VERSION 5.8 ;
BUSBITCHARS "[]" ;
DIVIDERCHAR "/" ;
UNITS
    DATABASE MICRONS 1000 ;
END UNITS

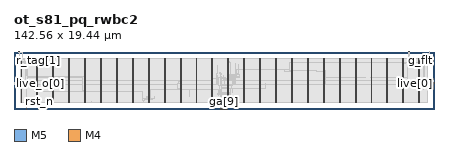
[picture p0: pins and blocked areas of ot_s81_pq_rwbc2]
MACRO ot_s81_pq_rwbc2
  FOREIGN ot_s81_pq_rwbc2 0 0 ;
  CLASS BLOCK ;
  SIZE 142.56 BY 19.44 ;
  PIN clk
    DIRECTION INPUT ;
    USE SIGNAL ;
    PORT
      LAYER M5 ;
        RECT  4.32 0 4.344 0.084 ;
    END
  END clk
  PIN g_flt
    DIRECTION INPUT ;
    USE SIGNAL ;
    PORT
      LAYER M5 ;
        RECT  141.12 19.356 141.144 19.44 ;
    END
  END g_flt
  PIN ga[0]
    DIRECTION OUTPUT ;
    USE SIGNAL ;
    PORT
      LAYER M5 ;
        RECT  70.128 0 70.152 0.084 ;
    END
  END ga[0]
  PIN ga[10]
    DIRECTION OUTPUT ;
    USE SIGNAL ;
    PORT
      LAYER M5 ;
        RECT  71.568 0 71.592 0.084 ;
    END
  END ga[10]
  PIN ga[11]
    DIRECTION OUTPUT ;
    USE SIGNAL ;
    PORT
      LAYER M5 ;
        RECT  71.712 0 71.736 0.084 ;
    END
  END ga[11]
  PIN ga[12]
    DIRECTION OUTPUT ;
    USE SIGNAL ;
    PORT
      LAYER M5 ;
        RECT  71.856 0 71.88 0.084 ;
    END
  END ga[12]
  PIN ga[13]
    DIRECTION OUTPUT ;
    USE SIGNAL ;
    PORT
      LAYER M5 ;
        RECT  72 0 72.024 0.084 ;
    END
  END ga[13]
  PIN ga[14]
    DIRECTION OUTPUT ;
    USE SIGNAL ;
    PORT
      LAYER M5 ;
        RECT  72.144 0 72.168 0.084 ;
    END
  END ga[14]
  PIN ga[15]
    DIRECTION OUTPUT ;
    USE SIGNAL ;
    PORT
      LAYER M5 ;
        RECT  72.288 0 72.312 0.084 ;
    END
  END ga[15]
  PIN ga[1]
    DIRECTION OUTPUT ;
    USE SIGNAL ;
    PORT
      LAYER M5 ;
        RECT  70.272 0 70.296 0.084 ;
    END
  END ga[1]
  PIN ga[2]
    DIRECTION OUTPUT ;
    USE SIGNAL ;
    PORT
      LAYER M5 ;
        RECT  70.416 0 70.44 0.084 ;
    END
  END ga[2]
  PIN ga[3]
    DIRECTION OUTPUT ;
    USE SIGNAL ;
    PORT
      LAYER M5 ;
        RECT  70.56 0 70.584 0.084 ;
    END
  END ga[3]
  PIN ga[4]
    DIRECTION OUTPUT ;
    USE SIGNAL ;
    PORT
      LAYER M5 ;
        RECT  70.704 0 70.728 0.084 ;
    END
  END ga[4]
  PIN ga[5]
    DIRECTION OUTPUT ;
    USE SIGNAL ;
    PORT
      LAYER M5 ;
        RECT  70.848 0 70.872 0.084 ;
    END
  END ga[5]
  PIN ga[6]
    DIRECTION OUTPUT ;
    USE SIGNAL ;
    PORT
      LAYER M5 ;
        RECT  70.992 0 71.016 0.084 ;
    END
  END ga[6]
  PIN ga[7]
    DIRECTION OUTPUT ;
    USE SIGNAL ;
    PORT
      LAYER M5 ;
        RECT  71.136 0 71.16 0.084 ;
    END
  END ga[7]
  PIN ga[8]
    DIRECTION OUTPUT ;
    USE SIGNAL ;
    PORT
      LAYER M5 ;
        RECT  71.28 0 71.304 0.084 ;
    END
  END ga[8]
  PIN ga[9]
    DIRECTION OUTPUT ;
    USE SIGNAL ;
    PORT
      LAYER M5 ;
        RECT  71.424 0 71.448 0.084 ;
    END
  END ga[9]
  PIN live[0]
    DIRECTION INPUT ;
    USE SIGNAL ;
    PORT
      LAYER M4 ;
        RECT  142.476 8.64 142.56 8.664 ;
    END
  END live[0]
  PIN live[1]
    DIRECTION INPUT ;
    USE SIGNAL ;
    PORT
      LAYER M4 ;
        RECT  142.476 8.784 142.56 8.808 ;
    END
  END live[1]
  PIN live[2]
    DIRECTION INPUT ;
    USE SIGNAL ;
    PORT
      LAYER M4 ;
        RECT  142.476 8.928 142.56 8.952 ;
    END
  END live[2]
  PIN live[3]
    DIRECTION INPUT ;
    USE SIGNAL ;
    PORT
      LAYER M4 ;
        RECT  142.476 9.072 142.56 9.096 ;
    END
  END live[3]
  PIN live_o[0]
    DIRECTION OUTPUT ;
    USE SIGNAL ;
    PORT
      LAYER M4 ;
        RECT  0 8.64 0.084 8.664 ;
    END
  END live_o[0]
  PIN live_o[1]
    DIRECTION OUTPUT ;
    USE SIGNAL ;
    PORT
      LAYER M4 ;
        RECT  0 8.784 0.084 8.808 ;
    END
  END live_o[1]
  PIN live_o[2]
    DIRECTION OUTPUT ;
    USE SIGNAL ;
    PORT
      LAYER M4 ;
        RECT  0 8.928 0.084 8.952 ;
    END
  END live_o[2]
  PIN live_o[3]
    DIRECTION OUTPUT ;
    USE SIGNAL ;
    PORT
      LAYER M4 ;
        RECT  0 9.072 0.084 9.096 ;
    END
  END live_o[3]
  PIN q2f
    DIRECTION OUTPUT ;
    USE SIGNAL ;
    PORT
      LAYER M5 ;
        RECT  72.432 0 72.456 0.084 ;
    END
  END q2f
  PIN r_e[0]
    DIRECTION INPUT ;
    USE SIGNAL ;
    PORT
      LAYER M5 ;
        RECT  1.968 19.356 1.992 19.44 ;
    END
  END r_e[0]
  PIN r_e[1]
    DIRECTION INPUT ;
    USE SIGNAL ;
    PORT
      LAYER M5 ;
        RECT  134.256 19.356 134.28 19.44 ;
    END
  END r_e[1]
  PIN r_tag[0]
    DIRECTION INPUT ;
    USE SIGNAL ;
    PORT
      LAYER M5 ;
        RECT  1.776 19.356 1.8 19.44 ;
    END
  END r_tag[0]
  PIN r_tag[1]
    DIRECTION INPUT ;
    USE SIGNAL ;
    PORT
      LAYER M5 ;
        RECT  1.872 19.356 1.896 19.44 ;
    END
  END r_tag[1]
  PIN r_tag[2]
    DIRECTION INPUT ;
    USE SIGNAL ;
    PORT
      LAYER M5 ;
        RECT  134.064 19.356 134.088 19.44 ;
    END
  END r_tag[2]
  PIN r_tag[3]
    DIRECTION INPUT ;
    USE SIGNAL ;
    PORT
      LAYER M5 ;
        RECT  134.16 19.356 134.184 19.44 ;
    END
  END r_tag[3]
  PIN r_v[0]
    DIRECTION INPUT ;
    USE SIGNAL ;
    PORT
      LAYER M5 ;
        RECT  1.68 19.356 1.704 19.44 ;
    END
  END r_v[0]
  PIN r_v[1]
    DIRECTION INPUT ;
    USE SIGNAL ;
    PORT
      LAYER M5 ;
        RECT  133.968 19.356 133.992 19.44 ;
    END
  END r_v[1]
  PIN rst_n
    DIRECTION INPUT ;
    USE SIGNAL ;
    PORT
      LAYER M5 ;
        RECT  8.64 0 8.664 0.084 ;
    END
  END rst_n
  PIN VDD
    DIRECTION INOUT ;
    USE POWER ;
    PORT
      LAYER M5 ;
        RECT  137.592 2.151 137.712 17.289 ;
        RECT  132.192 2.151 132.312 17.289 ;
        RECT  126.792 2.151 126.912 17.289 ;
        RECT  121.392 2.151 121.512 17.289 ;
        RECT  115.992 2.151 116.112 17.289 ;
        RECT  110.592 2.151 110.712 17.289 ;
        RECT  105.192 2.151 105.312 17.289 ;
        RECT  99.792 2.151 99.912 17.289 ;
        RECT  94.392 2.151 94.512 17.289 ;
        RECT  88.992 2.151 89.112 17.289 ;
        RECT  83.592 2.151 83.712 17.289 ;
        RECT  78.192 2.151 78.312 17.289 ;
        RECT  72.792 2.151 72.912 17.289 ;
        RECT  67.392 2.151 67.512 17.289 ;
        RECT  61.992 2.151 62.112 17.289 ;
        RECT  56.592 2.151 56.712 17.289 ;
        RECT  51.192 2.151 51.312 17.289 ;
        RECT  45.792 2.151 45.912 17.289 ;
        RECT  40.392 2.151 40.512 17.289 ;
        RECT  34.992 2.151 35.112 17.289 ;
        RECT  29.592 2.151 29.712 17.289 ;
        RECT  24.192 2.151 24.312 17.289 ;
        RECT  18.792 2.151 18.912 17.289 ;
        RECT  13.392 2.151 13.512 17.289 ;
        RECT  7.992 2.151 8.112 17.289 ;
        RECT  2.592 2.151 2.712 17.289 ;
    END
  END VDD
  PIN VSS
    DIRECTION INOUT ;
    USE GROUND ;
    PORT
      LAYER M5 ;
        RECT  137.4 2.137 137.52 17.303 ;
        RECT  132 2.137 132.12 17.303 ;
        RECT  126.6 2.137 126.72 17.303 ;
        RECT  121.2 2.137 121.32 17.303 ;
        RECT  115.8 2.137 115.92 17.303 ;
        RECT  110.4 2.137 110.52 17.303 ;
        RECT  105 2.137 105.12 17.303 ;
        RECT  99.6 2.137 99.72 17.303 ;
        RECT  94.2 2.137 94.32 17.303 ;
        RECT  88.8 2.137 88.92 17.303 ;
        RECT  83.4 2.137 83.52 17.303 ;
        RECT  78 2.137 78.12 17.303 ;
        RECT  72.6 2.137 72.72 17.303 ;
        RECT  67.2 2.137 67.32 17.303 ;
        RECT  61.8 2.137 61.92 17.303 ;
        RECT  56.4 2.137 56.52 17.303 ;
        RECT  51 2.137 51.12 17.303 ;
        RECT  45.6 2.137 45.72 17.303 ;
        RECT  40.2 2.137 40.32 17.303 ;
        RECT  34.8 2.137 34.92 17.303 ;
        RECT  29.4 2.137 29.52 17.303 ;
        RECT  24 2.137 24.12 17.303 ;
        RECT  18.6 2.137 18.72 17.303 ;
        RECT  13.2 2.137 13.32 17.303 ;
        RECT  7.8 2.137 7.92 17.303 ;
        RECT  2.4 2.137 2.52 17.303 ;
    END
  END VSS
  OBS
    LAYER RVTN ;
     RECT  2.16 2.16 140.4 2.295 ;
     RECT  2.16 2.565 140.4 2.835 ;
     RECT  2.16 3.105 140.4 3.375 ;
     RECT  2.16 3.645 140.4 3.915 ;
     RECT  2.16 4.185 140.4 4.455 ;
     RECT  2.16 4.725 140.4 4.995 ;
     RECT  2.16 5.265 140.4 5.535 ;
     RECT  2.16 5.805 140.4 6.075 ;
     RECT  2.16 6.345 140.4 6.615 ;
     RECT  2.16 6.885 140.4 7.155 ;
     RECT  2.16 7.425 140.4 7.695 ;
     RECT  2.16 7.965 140.4 8.235 ;
     RECT  2.16 8.505 140.4 8.775 ;
     RECT  2.16 9.045 140.4 9.315 ;
     RECT  2.16 9.585 140.4 9.855 ;
     RECT  2.16 10.125 140.4 10.395 ;
     RECT  2.16 10.665 140.4 10.935 ;
     RECT  2.16 11.205 140.4 11.475 ;
     RECT  2.16 11.745 140.4 12.015 ;
     RECT  2.16 12.285 140.4 12.555 ;
     RECT  2.16 12.825 140.4 13.095 ;
     RECT  2.16 13.365 140.4 13.635 ;
     RECT  2.16 13.905 140.4 14.175 ;
     RECT  2.16 14.445 140.4 14.715 ;
     RECT  2.16 14.985 140.4 15.255 ;
     RECT  2.16 15.525 140.4 15.795 ;
     RECT  2.16 16.065 140.4 16.335 ;
     RECT  2.16 16.605 140.4 16.875 ;
     RECT  2.16 17.145 140.4 17.28 ;
    LAYER RVTP ;
     RECT  2.16 2.295 140.4 2.565 ;
     RECT  2.16 2.835 140.4 3.105 ;
     RECT  2.16 3.375 140.4 3.645 ;
     RECT  2.16 3.915 140.4 4.185 ;
     RECT  2.16 4.455 140.4 4.725 ;
     RECT  2.16 4.995 140.4 5.265 ;
     RECT  2.16 5.535 140.4 5.805 ;
     RECT  2.16 6.075 140.4 6.345 ;
     RECT  2.16 6.615 140.4 6.885 ;
     RECT  2.16 7.155 140.4 7.425 ;
     RECT  2.16 7.695 140.4 7.965 ;
     RECT  2.16 8.235 140.4 8.505 ;
     RECT  2.16 8.775 140.4 9.045 ;
     RECT  2.16 9.315 140.4 9.585 ;
     RECT  2.16 9.855 140.4 10.125 ;
     RECT  2.16 10.395 140.4 10.665 ;
     RECT  2.16 10.935 140.4 11.205 ;
     RECT  2.16 11.475 140.4 11.745 ;
     RECT  2.16 12.015 140.4 12.285 ;
     RECT  2.16 12.555 140.4 12.825 ;
     RECT  2.16 13.095 140.4 13.365 ;
     RECT  2.16 13.635 140.4 13.905 ;
     RECT  2.16 14.175 140.4 14.445 ;
     RECT  2.16 14.715 140.4 14.985 ;
     RECT  2.16 15.255 140.4 15.525 ;
     RECT  2.16 15.795 140.4 16.065 ;
     RECT  2.16 16.335 140.4 16.605 ;
     RECT  2.16 16.875 140.4 17.145 ;
    LAYER M1 ;
     RECT  2.16 2.151 140.4 17.289 ;
    LAYER M2 ;
     RECT  0.103 8.316 0.535 8.334 ;
     RECT  0.535 8.316 2.16 8.532 ;
     RECT  2.16 2.151 140.4 17.289 ;
     RECT  140.4 16.92 140.819 16.938 ;
     RECT  140.4 9.09 141.179 9.576 ;
     RECT  141.179 9.558 142.403 9.576 ;
    LAYER M3 ;
     RECT  70.056 0.091 72.27 1.147 ;
     RECT  70.056 1.147 72.306 1.723 ;
     RECT  70.056 1.723 72.486 2.143 ;
     RECT  70.056 2.143 72.705 2.191 ;
     RECT  70.056 2.191 73.026 2.263 ;
     RECT  17.424 2.227 17.442 2.285 ;
     RECT  22.824 2.191 22.842 2.291 ;
     RECT  70.056 2.263 73.638 2.335 ;
     RECT  69.768 2.335 73.638 2.371 ;
     RECT  2.415 2.143 2.505 2.413 ;
     RECT  7.815 2.143 7.905 2.413 ;
     RECT  13.215 2.143 13.305 2.413 ;
     RECT  18.615 2.143 18.705 2.413 ;
     RECT  24.015 2.143 24.105 2.413 ;
     RECT  29.415 2.143 29.505 2.413 ;
     RECT  34.815 2.143 34.905 2.413 ;
     RECT  40.215 2.143 40.305 2.413 ;
     RECT  45.615 2.143 45.705 2.413 ;
     RECT  51.015 2.143 51.105 2.413 ;
     RECT  56.415 2.143 56.505 2.413 ;
     RECT  61.815 2.143 61.905 2.413 ;
     RECT  67.215 2.143 67.305 2.413 ;
     RECT  78.015 2.143 78.105 2.413 ;
     RECT  83.415 2.143 83.505 2.413 ;
     RECT  88.815 2.143 88.905 2.413 ;
     RECT  94.215 2.143 94.305 2.413 ;
     RECT  99.615 2.143 99.705 2.413 ;
     RECT  105.015 2.143 105.105 2.413 ;
     RECT  110.415 2.143 110.505 2.413 ;
     RECT  115.815 2.143 115.905 2.413 ;
     RECT  121.215 2.143 121.305 2.413 ;
     RECT  126.615 2.143 126.705 2.413 ;
     RECT  132.015 2.143 132.105 2.413 ;
     RECT  137.415 2.143 137.505 2.413 ;
     RECT  26.352 2.371 26.37 2.525 ;
     RECT  44.1 2.641 44.118 2.795 ;
     RECT  45.615 2.413 45.897 3.073 ;
     RECT  43.56 3.037 43.578 3.101 ;
     RECT  44.316 2.911 44.442 3.109 ;
     RECT  45.615 3.073 46.422 3.109 ;
     RECT  44.316 3.109 46.422 3.181 ;
     RECT  44.316 3.181 46.89 3.335 ;
     RECT  44.424 3.335 46.89 3.371 ;
     RECT  69.48 2.371 73.638 3.371 ;
     RECT  44.892 3.371 46.89 3.415 ;
     RECT  44.892 3.415 47.214 3.451 ;
     RECT  44.892 3.451 47.682 3.569 ;
     RECT  44.892 3.569 46.422 3.605 ;
     RECT  70.128 3.371 73.638 3.725 ;
     RECT  70.164 3.725 73.638 3.839 ;
     RECT  44.892 3.605 46.386 3.875 ;
     RECT  47.664 3.569 47.682 3.875 ;
     RECT  45.072 3.875 46.386 4.109 ;
     RECT  47.7 3.991 47.718 4.109 ;
     RECT  70.272 3.839 73.638 4.109 ;
     RECT  45.072 4.109 46.278 4.145 ;
     RECT  70.272 4.109 73.602 4.379 ;
     RECT  69.3 4.495 69.318 4.891 ;
     RECT  70.272 4.379 73.53 4.891 ;
     RECT  69.3 4.891 73.53 4.919 ;
     RECT  69.3 4.919 73.422 5.071 ;
     RECT  69.228 5.071 73.422 5.117 ;
     RECT  69.3 5.117 73.422 5.645 ;
     RECT  24.015 2.413 24.297 5.881 ;
     RECT  23.364 5.881 24.93 6.029 ;
     RECT  23.364 6.029 24.297 6.269 ;
     RECT  56.415 2.413 56.697 6.511 ;
     RECT  61.815 2.413 62.097 6.511 ;
     RECT  67.215 2.413 67.497 6.511 ;
     RECT  59.544 4.081 59.562 6.575 ;
     RECT  69.3 5.645 69.642 6.575 ;
     RECT  61.815 6.511 62.766 6.611 ;
     RECT  66.744 6.511 67.497 6.611 ;
     RECT  69.516 6.575 69.642 6.611 ;
     RECT  55.476 6.523 55.494 6.691 ;
     RECT  56.415 6.511 57.006 6.701 ;
     RECT  55.44 6.691 55.494 6.809 ;
     RECT  85.284 6.808 85.302 6.811 ;
     RECT  55.44 6.809 55.458 6.845 ;
     RECT  70.38 5.645 73.422 6.961 ;
     RECT  74.16 5.611 74.178 6.961 ;
     RECT  84.924 6.811 85.302 6.989 ;
     RECT  70.38 6.961 74.178 7.079 ;
     RECT  85.284 6.989 85.302 7.079 ;
     RECT  69.624 6.611 69.642 7.897 ;
     RECT  70.38 7.079 73.746 7.897 ;
     RECT  69.624 7.897 73.746 7.963 ;
     RECT  69.48 7.963 73.746 8.041 ;
     RECT  2.415 2.413 2.697 8.167 ;
     RECT  69.48 8.041 74.286 8.275 ;
     RECT  138.852 6.583 138.87 8.275 ;
     RECT  69.48 8.275 74.79 8.303 ;
     RECT  137.415 2.413 137.697 8.401 ;
     RECT  2.415 8.167 2.934 8.437 ;
     RECT  139.644 8.401 139.662 8.437 ;
     RECT  137.415 8.401 137.97 8.477 ;
     RECT  0.108 8.311 0.126 8.509 ;
     RECT  0.108 8.509 0.558 8.669 ;
     RECT  139.644 8.437 139.806 8.669 ;
     RECT  88.815 2.413 89.097 8.671 ;
     RECT  99.615 2.413 99.897 8.671 ;
     RECT  83.415 2.413 83.697 8.683 ;
     RECT  137.415 8.477 137.79 8.707 ;
     RECT  88.704 8.671 89.097 8.717 ;
     RECT  0.54 8.669 0.558 8.813 ;
     RECT  46.728 8.683 46.746 8.813 ;
     RECT  4.5 8.443 4.518 8.815 ;
     RECT  43.056 8.779 43.074 8.816 ;
     RECT  4.356 8.815 4.518 8.827 ;
     RECT  138.744 8.275 138.87 8.827 ;
     RECT  69.552 8.303 74.79 8.851 ;
     RECT  137.376 8.707 137.79 8.879 ;
     RECT  2.415 8.437 3.294 8.923 ;
     RECT  7.056 8.539 7.074 8.923 ;
     RECT  2.376 8.923 3.294 8.941 ;
     RECT  83.415 8.683 83.79 8.941 ;
     RECT  138.672 8.827 138.87 8.941 ;
     RECT  138.672 8.941 139.23 8.969 ;
     RECT  36.684 8.941 36.702 9.005 ;
     RECT  139.968 8.779 140.058 9.005 ;
     RECT  2.304 8.941 3.294 9.013 ;
     RECT  4.356 8.827 4.698 9.013 ;
     RECT  69.552 8.851 74.826 9.041 ;
     RECT  139.968 9.005 139.986 9.041 ;
     RECT  83.415 8.941 83.898 9.053 ;
     RECT  2.304 9.013 4.698 9.085 ;
     RECT  36.36 9.067 36.378 9.113 ;
     RECT  141.156 8.923 141.174 9.113 ;
     RECT  78.015 2.413 78.297 9.121 ;
     RECT  2.304 9.085 5.13 9.149 ;
     RECT  45.615 4.145 45.897 9.163 ;
     RECT  51.015 2.413 51.297 9.163 ;
     RECT  56.415 6.701 56.697 9.163 ;
     RECT  61.815 6.611 62.097 9.163 ;
     RECT  67.215 6.611 67.497 9.163 ;
     RECT  41.472 8.815 41.49 9.197 ;
     RECT  137.376 8.879 137.697 9.205 ;
     RECT  4.644 9.149 5.13 9.239 ;
     RECT  78.015 9.121 78.642 9.239 ;
     RECT  104.256 9.115 104.274 9.239 ;
     RECT  137.304 9.205 137.697 9.245 ;
     RECT  6.912 8.923 7.074 9.275 ;
     RECT  45.504 9.163 45.897 9.275 ;
     RECT  50.904 9.163 51.297 9.275 ;
     RECT  56.304 9.163 56.697 9.275 ;
     RECT  61.704 9.163 62.097 9.275 ;
     RECT  67.104 9.163 67.497 9.275 ;
     RECT  134.532 9.121 134.55 9.275 ;
     RECT  69.552 9.041 70.578 9.311 ;
     RECT  71.388 9.041 74.826 9.319 ;
     RECT  99.504 8.671 99.897 9.341 ;
     RECT  69.552 9.311 70.47 9.355 ;
     RECT  7.815 2.413 8.097 9.391 ;
     RECT  105.015 2.413 105.297 9.391 ;
     RECT  138.852 8.969 139.23 9.391 ;
     RECT  71.388 9.319 75.078 9.419 ;
     RECT  67.215 9.275 67.497 9.481 ;
     RECT  69.048 9.355 70.47 9.509 ;
     RECT  58.5 9.499 58.518 9.545 ;
     RECT  69.048 9.509 70.11 9.581 ;
     RECT  142.38 9.067 142.398 9.581 ;
     RECT  7.272 9.391 8.097 9.629 ;
     RECT  138.852 9.391 139.302 9.629 ;
     RECT  67.215 9.481 68.094 9.661 ;
     RECT  105.015 9.391 105.714 9.677 ;
     RECT  67.215 9.661 68.274 9.779 ;
     RECT  69.48 9.581 70.11 9.779 ;
     RECT  71.388 9.419 74.97 9.787 ;
     RECT  2.304 9.149 3.762 9.815 ;
     RECT  68.256 9.779 68.274 9.931 ;
     RECT  2.415 9.815 3.762 10.057 ;
     RECT  4.644 9.239 4.662 10.057 ;
     RECT  2.415 10.057 4.662 10.121 ;
     RECT  71.352 9.787 74.97 10.165 ;
     RECT  71.244 10.165 75.042 10.229 ;
     RECT  68.256 9.931 68.706 10.253 ;
     RECT  69.516 9.779 70.11 10.363 ;
     RECT  69.516 10.363 70.434 10.471 ;
     RECT  71.244 10.229 71.622 10.471 ;
     RECT  72.504 10.229 75.042 10.499 ;
     RECT  121.215 2.413 121.497 10.561 ;
     RECT  68.688 10.253 68.706 10.589 ;
     RECT  69.516 10.471 71.622 10.589 ;
     RECT  69.624 10.589 71.514 10.625 ;
     RECT  119.304 10.597 119.322 10.637 ;
     RECT  120.852 10.561 121.497 10.637 ;
     RECT  69.624 10.625 70.434 10.661 ;
     RECT  72.504 10.499 74.214 10.733 ;
     RECT  74.988 10.499 75.042 10.741 ;
     RECT  76.536 10.705 76.554 10.741 ;
     RECT  13.215 2.413 13.497 10.831 ;
     RECT  22.104 10.831 22.122 10.843 ;
     RECT  71.244 10.625 71.478 10.859 ;
     RECT  13.104 10.831 13.497 10.877 ;
     RECT  21.996 10.843 22.122 10.877 ;
     RECT  69.948 10.661 70.218 10.895 ;
     RECT  72.576 10.733 74.214 10.967 ;
     RECT  74.988 10.741 76.626 10.967 ;
     RECT  21.996 10.877 22.014 11.039 ;
     RECT  72.615 10.967 74.214 11.275 ;
     RECT  74.988 10.967 75.618 11.275 ;
     RECT  76.536 10.967 76.626 11.281 ;
     RECT  71.244 10.859 71.262 11.399 ;
     RECT  72.615 11.275 75.618 11.399 ;
     RECT  76.536 11.281 76.698 11.543 ;
     RECT  70.2 10.895 70.218 11.551 ;
     RECT  72.615 11.399 74.106 11.669 ;
     RECT  76.536 11.543 76.554 11.669 ;
     RECT  72.615 11.669 73.746 11.705 ;
     RECT  75.312 11.399 75.618 11.821 ;
     RECT  75.312 11.821 76.158 11.885 ;
     RECT  70.2 11.551 70.326 11.939 ;
     RECT  68.832 11.419 68.85 11.947 ;
     RECT  68.832 11.947 68.994 11.975 ;
     RECT  69.912 12.019 69.93 12.091 ;
     RECT  69.804 12.091 69.93 12.479 ;
     RECT  69.804 12.479 69.822 12.515 ;
     RECT  94.215 2.413 94.497 12.859 ;
     RECT  99.615 9.341 99.897 12.991 ;
     RECT  94.215 12.859 94.662 13.037 ;
     RECT  99.504 12.991 99.897 13.037 ;
     RECT  102.6 12.859 102.618 13.037 ;
     RECT  93.384 13.051 93.402 13.091 ;
     RECT  91.836 12.859 91.854 13.297 ;
     RECT  91.764 13.297 91.854 13.331 ;
     RECT  91.764 13.331 91.782 13.373 ;
     RECT  68.976 11.975 68.994 14.639 ;
     RECT  76.14 11.885 76.158 14.639 ;
     RECT  76.068 14.791 76.086 15.017 ;
     RECT  134.604 14.881 134.622 15.025 ;
     RECT  130.536 14.989 130.554 15.089 ;
     RECT  3.96 10.121 4.662 15.163 ;
     RECT  134.424 15.025 134.622 15.421 ;
     RECT  3.492 15.163 4.662 15.449 ;
     RECT  75.312 11.885 75.33 15.557 ;
     RECT  132.015 2.413 132.297 15.565 ;
     RECT  3.492 15.449 4.626 15.601 ;
     RECT  72.615 11.705 73.53 15.629 ;
     RECT  3.42 15.601 4.626 15.719 ;
     RECT  138.852 9.629 139.194 15.719 ;
     RECT  132.015 15.565 133.002 15.763 ;
     RECT  133.812 15.421 134.622 15.763 ;
     RECT  132.015 15.763 134.622 15.773 ;
     RECT  137.415 9.245 137.697 15.787 ;
     RECT  133.488 15.773 134.622 15.821 ;
     RECT  138.852 15.719 138.87 15.827 ;
     RECT  2.415 10.121 2.697 15.871 ;
     RECT  3.42 15.719 3.834 15.871 ;
     RECT  137.415 15.787 137.898 15.871 ;
     RECT  138.744 15.835 138.762 15.871 ;
     RECT  4.608 15.719 4.626 15.989 ;
     RECT  137.415 15.871 138.762 15.989 ;
     RECT  72.615 15.629 73.206 16.097 ;
     RECT  130.536 16.069 130.554 16.169 ;
     RECT  2.415 15.871 3.834 16.259 ;
     RECT  2.415 16.259 3.654 16.645 ;
     RECT  133.488 15.821 133.83 16.681 ;
     RECT  134.604 15.821 134.622 16.681 ;
     RECT  133.488 16.681 134.622 16.799 ;
     RECT  137.415 15.989 138.078 16.979 ;
     RECT  7.815 9.629 8.097 17.027 ;
     RECT  13.215 10.877 13.497 17.027 ;
     RECT  18.615 2.413 18.897 17.027 ;
     RECT  24.015 6.269 24.297 17.027 ;
     RECT  29.415 2.413 29.697 17.027 ;
     RECT  34.815 2.413 35.097 17.027 ;
     RECT  40.215 2.413 40.497 17.027 ;
     RECT  45.615 9.275 45.897 17.027 ;
     RECT  51.015 9.275 51.297 17.027 ;
     RECT  56.415 9.275 56.697 17.027 ;
     RECT  61.815 9.275 62.097 17.027 ;
     RECT  67.215 9.779 67.497 17.027 ;
     RECT  72.615 16.097 72.897 17.027 ;
     RECT  78.015 9.239 78.297 17.027 ;
     RECT  83.415 9.053 83.697 17.027 ;
     RECT  88.815 8.717 89.097 17.027 ;
     RECT  94.215 13.037 94.497 17.027 ;
     RECT  99.615 13.037 99.897 17.027 ;
     RECT  105.015 9.677 105.297 17.027 ;
     RECT  110.415 2.413 110.697 17.027 ;
     RECT  115.815 2.413 116.097 17.027 ;
     RECT  121.215 10.637 121.497 17.027 ;
     RECT  126.615 2.413 126.897 17.027 ;
     RECT  132.015 15.773 132.297 17.027 ;
     RECT  137.415 16.979 137.697 17.027 ;
     RECT  2.268 16.645 3.654 17.069 ;
     RECT  133.668 16.799 134.514 17.069 ;
     RECT  2.268 17.069 2.862 17.077 ;
     RECT  133.956 17.069 134.298 17.117 ;
     RECT  133.956 17.117 134.226 17.165 ;
     RECT  7.815 17.027 7.905 17.297 ;
     RECT  13.215 17.027 13.305 17.297 ;
     RECT  18.615 17.027 18.705 17.297 ;
     RECT  24.015 17.027 24.105 17.297 ;
     RECT  29.415 17.027 29.505 17.297 ;
     RECT  34.815 17.027 34.905 17.297 ;
     RECT  40.215 17.027 40.305 17.297 ;
     RECT  45.615 17.027 45.705 17.297 ;
     RECT  51.015 17.027 51.105 17.297 ;
     RECT  56.415 17.027 56.505 17.297 ;
     RECT  61.815 17.027 61.905 17.297 ;
     RECT  67.215 17.027 67.305 17.297 ;
     RECT  72.615 17.027 72.705 17.297 ;
     RECT  78.015 17.027 78.105 17.297 ;
     RECT  83.415 17.027 83.505 17.297 ;
     RECT  88.815 17.027 88.905 17.297 ;
     RECT  94.215 17.027 94.305 17.297 ;
     RECT  99.615 17.027 99.705 17.297 ;
     RECT  105.015 17.027 105.105 17.297 ;
     RECT  110.415 17.027 110.505 17.297 ;
     RECT  115.815 17.027 115.905 17.297 ;
     RECT  121.215 17.027 121.305 17.297 ;
     RECT  126.615 17.027 126.705 17.297 ;
     RECT  132.015 17.027 132.105 17.297 ;
     RECT  137.415 17.027 137.505 17.297 ;
     RECT  2.232 17.077 2.862 17.357 ;
     RECT  133.956 17.165 134.01 17.549 ;
     RECT  133.956 17.549 133.974 17.645 ;
     RECT  140.796 16.915 140.814 18.845 ;
     RECT  2.844 17.357 2.862 19.325 ;
    LAYER M4 ;
     RECT  0.06 8.64 0.137 9.096 ;
     RECT  0.137 8.784 0.569 9.096 ;
     RECT  1.765 17.088 1.861 17.112 ;
     RECT  1.861 17.088 2.261 17.352 ;
     RECT  0.569 8.928 2.408 9.096 ;
     RECT  2.261 17.088 2.408 17.292 ;
     RECT  2.408 2.148 2.512 17.292 ;
     RECT  2.512 2.418 2.704 17.022 ;
     RECT  1.669 19.296 2.873 19.32 ;
     RECT  2.704 15.168 4.259 15.192 ;
     RECT  4.309 9.312 4.46 9.336 ;
     RECT  4.46 9.072 4.489 9.336 ;
     RECT  4.213 11.376 4.501 11.4 ;
     RECT  4.501 10.848 4.547 11.4 ;
     RECT  4.489 8.448 7.261 9.336 ;
     RECT  6.901 6 7.808 6.024 ;
     RECT  7.261 8.448 7.808 9.624 ;
     RECT  4.547 10.848 7.808 10.872 ;
     RECT  7.808 2.148 7.912 17.292 ;
     RECT  7.912 2.256 8.104 17.022 ;
     RECT  8.104 2.256 13.208 2.28 ;
     RECT  8.104 6 13.208 6.024 ;
     RECT  8.104 8.448 13.208 9.624 ;
     RECT  8.104 10.848 13.208 10.872 ;
     RECT  13.208 2.148 13.312 17.292 ;
     RECT  13.312 2.256 13.504 17.022 ;
     RECT  13.504 2.256 17.453 2.28 ;
     RECT  13.504 6 18.608 6.024 ;
     RECT  13.504 8.448 18.608 9.624 ;
     RECT  13.504 10.848 18.608 10.872 ;
     RECT  18.608 2.148 18.712 17.292 ;
     RECT  18.712 2.418 18.904 17.022 ;
     RECT  18.904 6 23.353 6.024 ;
     RECT  23.353 6 24.008 6.264 ;
     RECT  18.904 8.448 24.008 9.624 ;
     RECT  18.904 10.848 24.008 10.872 ;
     RECT  24.008 2.148 24.112 17.292 ;
     RECT  24.112 2.418 24.304 17.022 ;
     RECT  24.304 6 29.408 6.024 ;
     RECT  24.304 8.448 29.408 9.624 ;
     RECT  29.408 2.148 29.512 17.292 ;
     RECT  29.512 2.418 29.704 17.022 ;
     RECT  29.704 6 34.808 6.024 ;
     RECT  29.704 8.448 34.808 9.624 ;
     RECT  34.808 2.148 34.912 17.292 ;
     RECT  34.912 2.418 35.104 17.022 ;
     RECT  35.104 6 40.208 6.024 ;
     RECT  35.104 8.448 40.208 9.624 ;
     RECT  40.208 2.148 40.312 17.292 ;
     RECT  40.312 2.418 40.504 17.022 ;
     RECT  40.504 6 43.571 6.024 ;
     RECT  43.525 3.072 43.612 3.624 ;
     RECT  43.612 3.6 45.608 3.624 ;
     RECT  40.504 8.448 45.608 9.624 ;
     RECT  45.608 2.148 45.712 17.292 ;
     RECT  45.712 2.418 45.904 17.022 ;
     RECT  45.904 3.408 46.355 3.432 ;
     RECT  45.904 6.528 51.008 6.552 ;
     RECT  45.904 8.448 51.008 9.624 ;
     RECT  51.008 2.148 51.112 17.292 ;
     RECT  51.112 2.418 51.304 17.022 ;
     RECT  51.304 6.528 55.429 6.552 ;
     RECT  55.429 6.528 56.408 6.84 ;
     RECT  51.304 8.448 56.408 9.624 ;
     RECT  56.408 2.148 56.512 17.292 ;
     RECT  56.512 2.418 56.704 17.022 ;
     RECT  56.704 6.528 57.017 6.696 ;
     RECT  57.017 6.528 61.808 6.552 ;
     RECT  56.704 8.448 61.808 9.624 ;
     RECT  61.808 2.148 61.912 17.292 ;
     RECT  61.912 2.418 62.104 17.022 ;
     RECT  62.104 6.528 67.093 6.552 ;
     RECT  67.093 6.528 67.208 6.648 ;
     RECT  62.104 8.448 67.208 9.624 ;
     RECT  67.208 2.148 67.312 17.292 ;
     RECT  67.312 2.418 67.504 17.022 ;
     RECT  67.504 8.448 68.677 10.248 ;
     RECT  68.677 8.448 68.821 10.584 ;
     RECT  68.821 8.448 68.905 11.448 ;
     RECT  68.905 8.448 69.469 10.584 ;
     RECT  69.217 5.088 69.932 5.112 ;
     RECT  69.932 5.088 70.019 5.64 ;
     RECT  69.469 7.968 70.189 10.584 ;
     RECT  70.045 0.096 70.261 0.12 ;
     RECT  69.973 3.696 70.261 3.72 ;
     RECT  70.189 7.968 70.265 10.872 ;
     RECT  70.265 8.448 70.307 10.872 ;
     RECT  67.504 6.624 70.445 6.648 ;
     RECT  70.261 0.096 70.451 0.168 ;
     RECT  70.508 7.2 70.595 7.464 ;
     RECT  70.261 3.408 70.657 3.72 ;
     RECT  70.657 3.408 70.739 3.864 ;
     RECT  70.739 3.696 70.945 3.864 ;
     RECT  70.117 1.728 71.165 1.752 ;
     RECT  70.307 8.448 71.341 9.624 ;
     RECT  70.451 0.096 71.413 0.12 ;
     RECT  71.413 0.096 71.561 0.6 ;
     RECT  71.561 0.096 71.749 0.168 ;
     RECT  70.945 3.696 71.809 4.536 ;
     RECT  70.595 7.44 71.809 7.464 ;
     RECT  71.845 1.152 72.269 1.176 ;
     RECT  71.989 2.16 72.269 2.184 ;
     RECT  71.749 0.096 72.281 0.12 ;
     RECT  72.269 1.152 72.317 2.184 ;
     RECT  71.809 3.552 72.469 4.536 ;
     RECT  72.317 1.728 72.497 2.184 ;
     RECT  72.497 2.148 72.608 2.184 ;
     RECT  72.469 3.552 72.608 4.776 ;
     RECT  71.809 6.816 72.608 7.464 ;
     RECT  71.341 8.448 72.608 9.816 ;
     RECT  72.608 2.148 72.712 17.292 ;
     RECT  72.712 2.418 72.904 17.022 ;
     RECT  72.904 10.896 73.253 10.92 ;
     RECT  72.904 8.448 74.101 9.816 ;
     RECT  74.101 8.448 74.509 10.584 ;
     RECT  74.509 8.448 74.629 11.304 ;
     RECT  74.629 8.448 74.675 11.688 ;
     RECT  74.675 8.448 75.017 10.584 ;
     RECT  74.675 11.664 75.548 11.688 ;
     RECT  75.548 11.664 75.629 11.88 ;
     RECT  75.629 11.856 75.635 11.88 ;
     RECT  72.904 6.816 78.008 6.84 ;
     RECT  75.017 8.448 78.008 9.624 ;
     RECT  75.589 13.344 78.008 13.368 ;
     RECT  78.008 2.148 78.112 17.292 ;
     RECT  78.112 2.418 78.304 17.022 ;
     RECT  78.304 6.816 83.408 6.84 ;
     RECT  78.304 8.448 83.408 9.624 ;
     RECT  78.304 13.344 83.408 13.368 ;
     RECT  83.408 2.148 83.512 17.292 ;
     RECT  83.512 2.418 83.704 17.022 ;
     RECT  83.704 6.816 85.331 6.84 ;
     RECT  83.704 8.448 88.808 9.624 ;
     RECT  83.704 13.344 88.808 13.368 ;
     RECT  88.808 2.148 88.912 17.292 ;
     RECT  88.912 2.418 89.104 17.022 ;
     RECT  89.104 13.344 91.825 13.368 ;
     RECT  91.825 12.864 91.826 13.368 ;
     RECT  89.104 8.448 94.208 9.624 ;
     RECT  91.826 12.864 94.208 13.32 ;
     RECT  93.397 15.744 94.208 15.768 ;
     RECT  94.208 2.148 94.312 17.292 ;
     RECT  94.312 2.418 94.504 17.022 ;
     RECT  94.504 12.864 94.673 13.032 ;
     RECT  94.504 8.448 99.608 9.624 ;
     RECT  94.673 13.008 99.608 13.032 ;
     RECT  94.504 15.744 99.608 15.768 ;
     RECT  99.608 2.148 99.712 17.292 ;
     RECT  99.712 2.418 99.904 17.022 ;
     RECT  99.904 13.008 102.589 13.032 ;
     RECT  102.589 12.864 102.629 13.032 ;
     RECT  99.904 8.448 105.008 9.624 ;
     RECT  102.629 12.864 105.008 12.888 ;
     RECT  99.904 15.744 105.008 15.768 ;
     RECT  105.008 2.148 105.112 17.292 ;
     RECT  105.112 2.418 105.304 17.022 ;
     RECT  105.304 12.864 105.731 12.888 ;
     RECT  105.304 8.448 105.769 10.632 ;
     RECT  105.769 8.448 110.408 9.624 ;
     RECT  105.769 10.608 110.408 10.632 ;
     RECT  105.304 15.744 110.408 15.768 ;
     RECT  110.408 2.148 110.512 17.292 ;
     RECT  110.512 2.418 110.704 17.022 ;
     RECT  110.704 8.448 115.808 9.624 ;
     RECT  110.704 10.608 115.808 10.632 ;
     RECT  110.704 15.744 115.808 15.768 ;
     RECT  115.808 2.148 115.912 17.292 ;
     RECT  115.912 2.418 116.104 17.022 ;
     RECT  116.104 10.608 119.333 10.632 ;
     RECT  116.104 8.448 121.208 9.624 ;
     RECT  120.841 10.608 121.208 10.632 ;
     RECT  116.104 15.744 121.208 15.768 ;
     RECT  121.208 2.148 121.312 17.292 ;
     RECT  121.312 2.418 121.504 17.022 ;
     RECT  121.504 8.448 126.608 9.624 ;
     RECT  121.504 10.608 126.608 10.632 ;
     RECT  121.504 15.744 126.608 15.768 ;
     RECT  126.608 2.148 126.712 17.292 ;
     RECT  126.712 2.418 126.904 17.022 ;
     RECT  126.904 8.448 132.008 9.624 ;
     RECT  126.904 10.608 132.008 10.632 ;
     RECT  126.904 15.744 132.008 15.768 ;
     RECT  132.008 2.148 132.112 17.292 ;
     RECT  132.112 2.418 132.304 17.022 ;
     RECT  132.304 15.744 133.013 15.768 ;
     RECT  132.304 10.608 133.667 10.632 ;
     RECT  133.937 17.52 133.945 17.544 ;
     RECT  133.945 17.52 134.099 17.64 ;
     RECT  134.149 17.136 134.245 17.16 ;
     RECT  134.245 17.088 134.246 17.16 ;
     RECT  134.246 17.088 134.332 17.112 ;
     RECT  132.304 8.448 137.408 9.624 ;
     RECT  133.513 15.792 137.408 15.816 ;
     RECT  137.408 2.148 137.512 17.292 ;
     RECT  137.512 2.418 137.704 17.022 ;
     RECT  137.704 15.792 137.909 15.816 ;
     RECT  137.704 8.448 139.313 9.624 ;
     RECT  139.313 8.448 139.673 8.808 ;
     RECT  139.673 8.64 141.145 8.808 ;
     RECT  140.785 18.816 141.155 18.84 ;
     RECT  141.145 8.64 142.369 8.952 ;
     RECT  142.369 8.64 142.524 9.096 ;
    LAYER M5 ;
     RECT  70.128 0.016 72.456 1.187 ;
     RECT  70.128 1.187 71.016 1.763 ;
     RECT  8.64 0.016 8.664 2.137 ;
     RECT  72 1.187 72.456 2.137 ;
     RECT  2.4 2.137 2.52 2.151 ;
     RECT  13.2 2.137 13.32 2.151 ;
     RECT  18.6 2.137 18.72 2.151 ;
     RECT  24 2.137 24.12 2.151 ;
     RECT  29.4 2.137 29.52 2.151 ;
     RECT  34.8 2.137 34.92 2.151 ;
     RECT  40.2 2.137 40.32 2.151 ;
     RECT  45.6 2.137 45.72 2.151 ;
     RECT  51 2.137 51.12 2.151 ;
     RECT  56.4 2.137 56.52 2.151 ;
     RECT  61.8 2.137 61.92 2.151 ;
     RECT  67.2 2.137 67.32 2.151 ;
     RECT  72 2.137 72.72 2.151 ;
     RECT  78 2.137 78.12 2.151 ;
     RECT  83.4 2.137 83.52 2.151 ;
     RECT  88.8 2.137 88.92 2.151 ;
     RECT  94.2 2.137 94.32 2.151 ;
     RECT  99.6 2.137 99.72 2.151 ;
     RECT  105 2.137 105.12 2.151 ;
     RECT  110.4 2.137 110.52 2.151 ;
     RECT  115.8 2.137 115.92 2.151 ;
     RECT  121.2 2.137 121.32 2.151 ;
     RECT  126.6 2.137 126.72 2.151 ;
     RECT  132 2.137 132.12 2.151 ;
     RECT  137.4 2.137 137.52 2.151 ;
     RECT  72 2.151 72.912 2.195 ;
     RECT  7.8 2.137 8.664 2.291 ;
     RECT  45.6 2.151 45.912 3.397 ;
     RECT  70.704 1.763 70.728 3.443 ;
     RECT  72.6 2.195 72.912 4.741 ;
     RECT  7.8 2.291 8.112 5.989 ;
     RECT  43.536 3.061 43.56 6.035 ;
     RECT  24 2.151 24.312 6.229 ;
     RECT  67.2 2.151 67.512 6.517 ;
     RECT  45.6 3.397 46.344 6.563 ;
     RECT  67.104 6.517 67.512 6.659 ;
     RECT  69.984 3.685 70.008 6.659 ;
     RECT  56.4 2.151 56.712 6.805 ;
     RECT  72.48 4.741 72.912 6.851 ;
     RECT  70.56 7.189 70.584 7.957 ;
     RECT  70.128 7.957 70.584 8.627 ;
     RECT  55.44 6.805 56.712 8.723 ;
     RECT  85.296 6.805 85.32 8.723 ;
     RECT  6.912 5.989 8.112 8.963 ;
     RECT  4.32 0.016 4.344 9.061 ;
     RECT  72.6 6.851 72.912 9.061 ;
     RECT  4.32 9.061 4.536 9.347 ;
     RECT  55.68 8.723 56.712 9.443 ;
     RECT  105 2.151 105.312 9.637 ;
     RECT  72.384 9.061 72.912 9.827 ;
     RECT  70.128 8.627 70.152 10.549 ;
     RECT  74.112 9.637 74.136 10.549 ;
     RECT  70.128 10.549 70.296 10.595 ;
     RECT  74.112 10.549 74.664 10.595 ;
     RECT  23.376 6.229 24.312 10.883 ;
     RECT  70.272 10.595 70.296 10.883 ;
     RECT  4.512 9.347 4.536 11.365 ;
     RECT  4.224 11.365 4.536 11.411 ;
     RECT  68.832 10.549 68.856 11.459 ;
     RECT  74.64 10.595 74.664 11.699 ;
     RECT  105 9.637 105.72 12.899 ;
     RECT  94.2 2.151 94.512 13.045 ;
     RECT  75.6 11.845 75.624 13.379 ;
     RECT  4.224 11.411 4.248 15.203 ;
     RECT  93.408 13.045 94.512 15.779 ;
     RECT  133.632 9.205 133.656 15.827 ;
     RECT  2.4 2.151 2.712 17.077 ;
     RECT  134.256 17.077 134.28 17.125 ;
     RECT  1.776 17.077 2.712 17.289 ;
     RECT  7.8 8.963 8.112 17.289 ;
     RECT  13.2 2.151 13.512 17.289 ;
     RECT  18.6 2.151 18.912 17.289 ;
     RECT  24 10.883 24.312 17.289 ;
     RECT  29.4 2.151 29.712 17.289 ;
     RECT  34.8 2.151 35.112 17.289 ;
     RECT  40.2 2.151 40.512 17.289 ;
     RECT  45.6 6.563 45.912 17.289 ;
     RECT  51 2.151 51.312 17.289 ;
     RECT  56.4 9.443 56.712 17.289 ;
     RECT  61.8 2.151 62.112 17.289 ;
     RECT  67.2 6.659 67.512 17.289 ;
     RECT  72.6 9.827 72.912 17.289 ;
     RECT  78 2.151 78.312 17.289 ;
     RECT  83.4 2.151 83.712 17.289 ;
     RECT  88.8 2.151 89.112 17.289 ;
     RECT  94.2 15.779 94.512 17.289 ;
     RECT  99.6 2.151 99.912 17.289 ;
     RECT  105 12.899 105.312 17.289 ;
     RECT  110.4 2.151 110.712 17.289 ;
     RECT  115.8 2.151 116.112 17.289 ;
     RECT  121.2 2.151 121.512 17.289 ;
     RECT  126.6 2.151 126.912 17.289 ;
     RECT  132 2.151 132.312 17.289 ;
     RECT  137.4 2.151 137.712 17.289 ;
     RECT  1.776 17.289 2.52 17.303 ;
     RECT  7.8 17.289 7.92 17.303 ;
     RECT  13.2 17.289 13.32 17.303 ;
     RECT  18.6 17.289 18.72 17.303 ;
     RECT  24 17.289 24.12 17.303 ;
     RECT  29.4 17.289 29.52 17.303 ;
     RECT  34.8 17.289 34.92 17.303 ;
     RECT  40.2 17.289 40.32 17.303 ;
     RECT  45.6 17.289 45.72 17.303 ;
     RECT  51 17.289 51.12 17.303 ;
     RECT  56.4 17.289 56.52 17.303 ;
     RECT  61.8 17.289 61.92 17.303 ;
     RECT  67.2 17.289 67.32 17.303 ;
     RECT  72.6 17.289 72.72 17.303 ;
     RECT  78 17.289 78.12 17.303 ;
     RECT  83.4 17.289 83.52 17.303 ;
     RECT  88.8 17.289 88.92 17.303 ;
     RECT  94.2 17.289 94.32 17.303 ;
     RECT  99.6 17.289 99.72 17.303 ;
     RECT  105 17.289 105.12 17.303 ;
     RECT  110.4 17.289 110.52 17.303 ;
     RECT  115.8 17.289 115.92 17.303 ;
     RECT  121.2 17.289 121.32 17.303 ;
     RECT  126.6 17.289 126.72 17.303 ;
     RECT  132 17.289 132.12 17.303 ;
     RECT  137.4 17.289 137.52 17.303 ;
     RECT  134.16 17.125 134.28 17.509 ;
     RECT  1.776 17.303 1.992 19.285 ;
     RECT  1.68 19.285 1.992 19.408 ;
     RECT  133.968 17.509 134.28 19.408 ;
     RECT  141.12 18.805 141.144 19.408 ;
  END
END ot_s81_pq_rwbc2
END LIBRARY
